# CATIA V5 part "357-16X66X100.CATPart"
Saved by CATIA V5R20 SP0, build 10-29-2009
Part number: 357-16X66X100
Definition: NONE
Nomenclature: 357-16X66X100
Source: Unknown
Description: 357-16X66X100
Bounding box of the stored display mesh (mm): x -15 to 85, y -13 to 13, z -13 to 13
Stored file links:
  C:\Users\Utente\Desktop\IO LAVORO\3D X SITO CF\X SITO\PLASTICA\357\357-16X66X100.CATPart

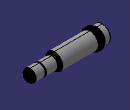
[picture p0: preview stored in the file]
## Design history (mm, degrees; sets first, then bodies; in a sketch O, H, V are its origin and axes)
Body1 "357-16X66X100" (main body)
  Solid1: solid without history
